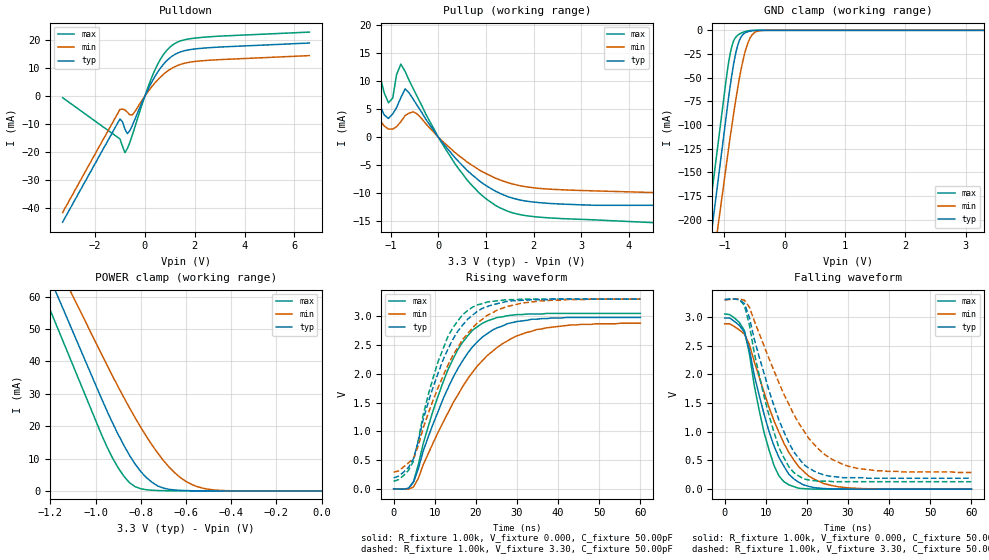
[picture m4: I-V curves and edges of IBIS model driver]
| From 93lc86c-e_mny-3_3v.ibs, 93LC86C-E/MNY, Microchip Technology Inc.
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|   Model driver
[Model]   driver
Model_type   3-state
Vmeas = 1.65
C_comp   5.00pF   5.00pF   5.00pF
[Temperature Range]   25.00   125.00   -40.00
[Voltage Range]   3.30V   2.50V   5.50V
[Pullup Reference]   3.30V   3.30V   3.30V
[POWER Clamp Reference]   3.30V   3.30V   3.30V
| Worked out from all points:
|   slope of the pulldown table from 0 to 0.495 V, typ, clamps not added: 59.7 ohm
|   slope of the pullup table from 0 to 0.495 V, typ, clamps not added: 100 ohm
|   GND clamp passes 1 mA (typ) near -0.59 V on its own axis
|   POWER clamp passes 1 mA (typ) near -0.70 V on its own axis
|   rising waveform, R_fixture 1.00k, V_fixture 0.000, C_fixture 50.00pF: 20-80 % time 11.3ns typ, 14.4ns min, 9.17ns max; typ from 0 V to 2.98 V
|   rising waveform, R_fixture 1.00k, V_fixture 3.30, C_fixture 50.00pF: 20-80 % time 9.14ns typ, 11.4ns min, 7.61ns max; typ from 0.19 V to 3.3 V
|   falling waveform, R_fixture 1.00k, V_fixture 0.000, C_fixture 50.00pF: 20-80 % time 6.8ns typ, 9.33ns min, 5.35ns max; typ from 2.98 V to 0 V
|   falling waveform, R_fixture 1.00k, V_fixture 3.30, C_fixture 50.00pF: 20-80 % time 8.6ns typ, 11.9ns min, 6.53ns max; typ from 3.3 V to 0.19 V
[GND_clamp]
| voltage   I(typ)   I(min)   I(max)
-3.3V     -1.265A    -1.234A    -1.229A
-1.345V   -279.6mA   -318.9mA   -240.8mA
-1.26V    -236.7mA   -279.1mA   -197.9mA
-1.175V   -193.9mA   -239.3mA   -155mA
-1.09V    -151.1mA   -199.5mA   -112mA
-950mV    -80.54mA   -133.9mA   -42.22mA
-900mV    -56.85mA   -110.8mA   -23.12mA
-800mV    -20.78mA   -68.96mA   -6.385mA
-725mV    -7.045mA   -41.67mA   -2.973mA
-575mV    -834uA     -8.114mA   -219uA
-425mV    -18.71uA   -567.5uA   -518.5nA
3.3V      10pA       10.57nA    10pA
[POWER_clamp]
| voltage   I(typ)   I(min)   I(max)
-3.3V     408.2mA    371.7mA    412mA
-1.225V   69.56mA    77.86mA    60.04mA
-1.175V   61.4mA     70.78mA    51.56mA
-1.15V    57.32mA    67.24mA    47.32mA
-1.1V     49.16mA    60.16mA    38.84mA
-975mV    28.76mA    42.46mA    17.64mA
-900mV    17.47mA    32.18mA    7.159mA
-825mV    8.309mA    22.62mA    1.312mA
-750mV    2.652mA    14.18mA    222.9uA
-625mV    176.9uA    4.127mA    10.67uA
-525mV    16.3uA     835.7uA    178nA
0V        10pA       5.145nA    10pA
[Pulldown]
| voltage   I(typ)   I(min)   I(max)
-3.3V     -44.94mA   -41.53mA   -543.3uA
-1V       -8.144mA   -4.733mA   -15.26mA
-900mV    -9.124mA   -4.633mA   -17.78mA
-800mV    -11.71mA   -4.913mA   -20.15mA
-700mV    -13.42mA   -5.763mA   -18.67mA
-500mV    -10.39mA   -6.681mA   -13.83mA
0V        0A         0A         0A
400mV     6.923mA    4.65mA     9.245mA
700mV     10.85mA    7.401mA    14.21mA
1.1V      14.27mA    10.01mA    18.15mA
2.2V      16.98mA    12.51mA    20.85mA
6.6V      18.93mA    14.44mA    22.82mA
[Pullup]
| voltage   I(typ)   I(min)   I(max)
-3.3V     46.2mA     27mA       81.28mA
-2.65V    33.5mA     19.48mA    59.24mA
-2V       20.8mA     11.96mA    37.21mA
-1.49V    10.63mA    5.942mA    19.57mA
-1.05V    3.352mA    1.456mA    6.145mA
-960mV    4.172mA    1.443mA    7.003mA
-790mV    7.078mA    2.755mA    13.06mA
-700mV    8.653mA    3.872mA    11.77mA
-440mV    5.584mA    4.105mA    7.142mA
430mV     -4.431mA   -3.307mA   -5.729mA
1.47V     -10.68mA   -8.173mA   -13.3mA
6.6V      -12.19mA   -10.41mA   -16.12mA
[Ramp]
| variable   typ   min   max
dV/dt_r   1.79/0.73n   1.73/0.90n   1.83/0.61n
dV/dt_f   1.86/0.94n   1.80/1.09n   1.90/0.60n
R_load = 1.00k
[Rising Waveform]
R_fixture = 1.00k
V_fixture = 0.000
C_fixture = 50.00pF
| time   V(typ)   V(min)   V(max)
0s        -49.93uV   -16.83uV   -99.5uV
3.6ns     9.57mV     -4.11mV    5.25mV
4.8ns     110mV      30.23mV    120mV
8.4ns     900mV      610mV      1.08V
12ns      1.56V      1.15V      1.85V
15.6ns    2.09V      1.63V      2.42V
19.2ns    2.47V      2.03V      2.76V
24ns      2.76V      2.39V      2.95V
32.4ns    2.93V      2.72V      3.04V
60ns      2.98V      2.88V      3.05V
[Rising Waveform]
R_fixture = 1.00k
V_fixture = 3.30
C_fixture = 50.00pF
| time   V(typ)   V(min)   V(max)
0s        190mV      290mV      130mV
2.4ns     290mV      380mV      230mV
4.8ns     520mV      530mV      480mV
7.2ns     1.21V      1.06V      1.29V
10.8ns    2.01V      1.76V      2.21V
14.4ns    2.6V       2.32V      2.8V
18ns      2.95V      2.7V       3.1V
22.8ns    3.17V      3.02V      3.25V
31.2ns    3.28V      3.23V      3.3V
60ns      3.3V       3.3V       3.3V
[Falling Waveform]
R_fixture = 1.00k
V_fixture = 0.000
C_fixture = 50.00pF
| time   V(typ)   V(min)   V(max)
0s        2.98V      2.88V      3.05V
2.4ns     2.92V      2.83V      2.98V
4.8ns     2.73V      2.7V       2.76V
6ns       2.43V      2.52V      2.36V
9.6ns     1.3V       1.68V      980mV
12ns      750mV      1.19V      410mV
14.4ns    400mV      800mV      130mV
18ns      120mV      390mV      16.03mV
25.2ns    7.1mV      77.97mV    160uV
60ns      48.51nV    14.15uV    46.19nV
[Falling Waveform]
R_fixture = 1.00k
V_fixture = 3.30
C_fixture = 50.00pF
| time   V(typ)   V(min)   V(max)
0s        3.3V       3.3V       3.3V
4.8ns     3.23V      3.29V      3.2V
6ns       2.99V      3.17V      2.86V
7.2ns     2.61V      2.93V      2.37V
10.8ns    1.71V      2.27V      1.28V
13.2ns    1.2V       1.85V      720mV
16.8ns    650mV      1.3V       290mV
22.8ns    280mV      700mV      140mV
30ns      200mV      400mV      130mV
60ns      190mV      290mV      130mV
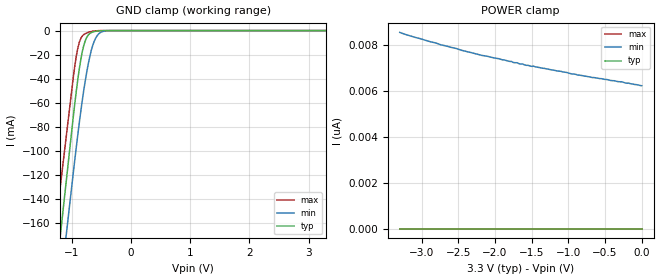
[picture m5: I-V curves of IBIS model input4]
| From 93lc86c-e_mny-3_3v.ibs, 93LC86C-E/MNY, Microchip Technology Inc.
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|   Model input4
[Model]   input4
Model_type   Input
Vinl = 0.8
Vinh = 2.0
C_comp   5.00pF   5.00pF   5.00pF
[Temperature Range]   25.00   125.00   -40.00
[Voltage Range]   3.30V   2.50V   5.50V
[Pullup Reference]   3.30V   3.30V   3.30V
[POWER Clamp Reference]   3.30V   3.30V   3.30V
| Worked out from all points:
|   GND clamp passes 1 mA (typ) near -0.64 V on its own axis
[GND_clamp]
| voltage   I(typ)   I(min)   I(max)
-3.3V     -1.115A    -1.121A    -995.6mA
-1.345V   -236.4mA   -276.6mA   -190.1mA
-1.26V    -198.2mA   -239.9mA   -155.1mA
-1.175V   -160.1mA   -203.2mA   -120.1mA
-1.09V    -121.9mA   -166.5mA   -85.06mA
-925mV    -49.41mA   -95.94mA   -20.61mA
-850mV    -23.81mA   -66.75mA   -6.427mA
-775mV    -8.364mA   -41.61mA   -2.531mA
-700mV    -2.465mA   -21.93mA   -1.119mA
-625mV    -861.5uA   -9.034mA   -352.1uA
-450mV    -21.25uA   -439.7uA   -2.911uA
3.3V      -67.28nA   -42.56nA   -87.39nA
[POWER_clamp]
| voltage   I(typ)   I(min)   I(max)
-3.3V     10pA       8.526nA    10pA
-3.09V    10pA       8.31nA     10pA
-2.46V    10pA       7.752nA    10pA
-2.18V    10pA       7.528nA    10pA
-1.775V   10pA       7.264nA    10pA
-1.75V    10pA       7.22nA     10pA
-1.7V     10pA       7.209nA    10pA
-1.575V   10pA       7.098nA    10pA
-875mV    10pA       6.677nA    10pA
-275mV    10pA       6.384nA    10pA
-225mV    10pA       6.332nA    10pA
0V        10pA       6.211nA    10pA
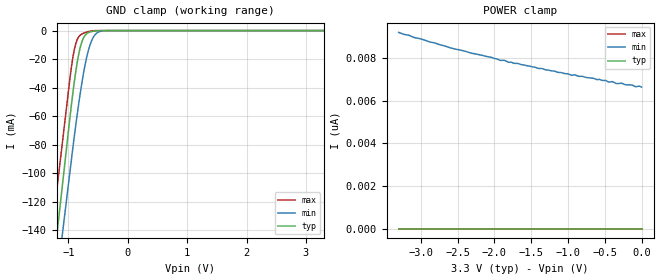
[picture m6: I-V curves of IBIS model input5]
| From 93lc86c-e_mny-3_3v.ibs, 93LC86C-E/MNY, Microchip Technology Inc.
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|   Model input5
[Model]   input5
Model_type   Input
Vinl = 0.8
Vinh = 2.0
C_comp   5.00pF   5.00pF   5.00pF
[Temperature Range]   25.00   125.00   -40.00
[Voltage Range]   3.30V   2.50V   5.50V
[Pullup Reference]   3.30V   3.30V   3.30V
[POWER Clamp Reference]   3.30V   3.30V   3.30V
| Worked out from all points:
|   GND clamp passes 1 mA (typ) near -0.64 V on its own axis
[GND_clamp]
| voltage   I(typ)   I(min)   I(max)
-3.3V     -931.6mA   -898.9mA   -855.9mA
-1.345V   -199.7mA   -226.4mA   -164.6mA
-1.26V    -167.9mA   -197.1mA   -134.5mA
-1.175V   -136mA     -167.9mA   -104.5mA
-1.09V    -104.2mA   -138.7mA   -74.39mA
-925mV    -43.69mA   -82.15mA   -18.88mA
-875mV    -28.4mA    -65.91mA   -9.012mA
-825mV    -16.25mA   -50.82mA   -4.315mA
-750mV    -5.447mA   -30.94mA   -1.925mA
-625mV    -857.7uA   -8.752mA   -342.5uA
-450mV    -19.96uA   -448.3uA   -792.4nA
3.3V      10pA       4.668nA    10pA
[POWER_clamp]
| voltage   I(typ)   I(min)   I(max)
-3.3V     10pA       9.201nA    10pA
-2.6V     10pA       8.478nA    10pA
-1.8V     10pA       7.798nA    10pA
-950mV    10pA       7.19nA     10pA
-900mV    10pA       7.21nA     10pA
-500mV    10pA       6.954nA    10pA
-450mV    10pA       6.874nA    10pA
-400mV    10pA       6.897nA    10pA
-350mV    10pA       6.81nA     10pA
-275mV    10pA       6.826nA    10pA
-225mV    10pA       6.753nA    10pA
0V        10pA       6.636nA    10pA
